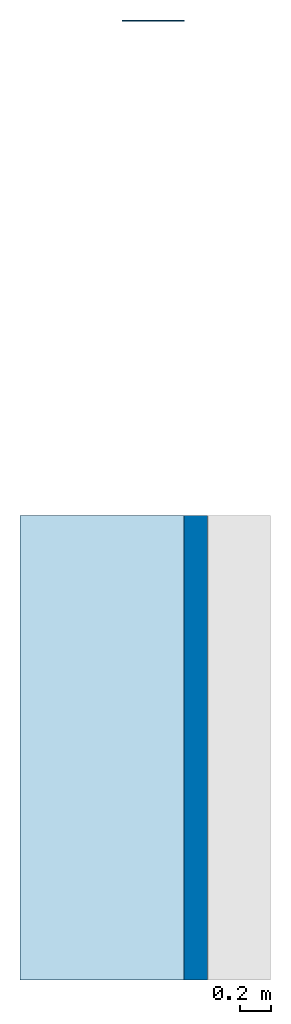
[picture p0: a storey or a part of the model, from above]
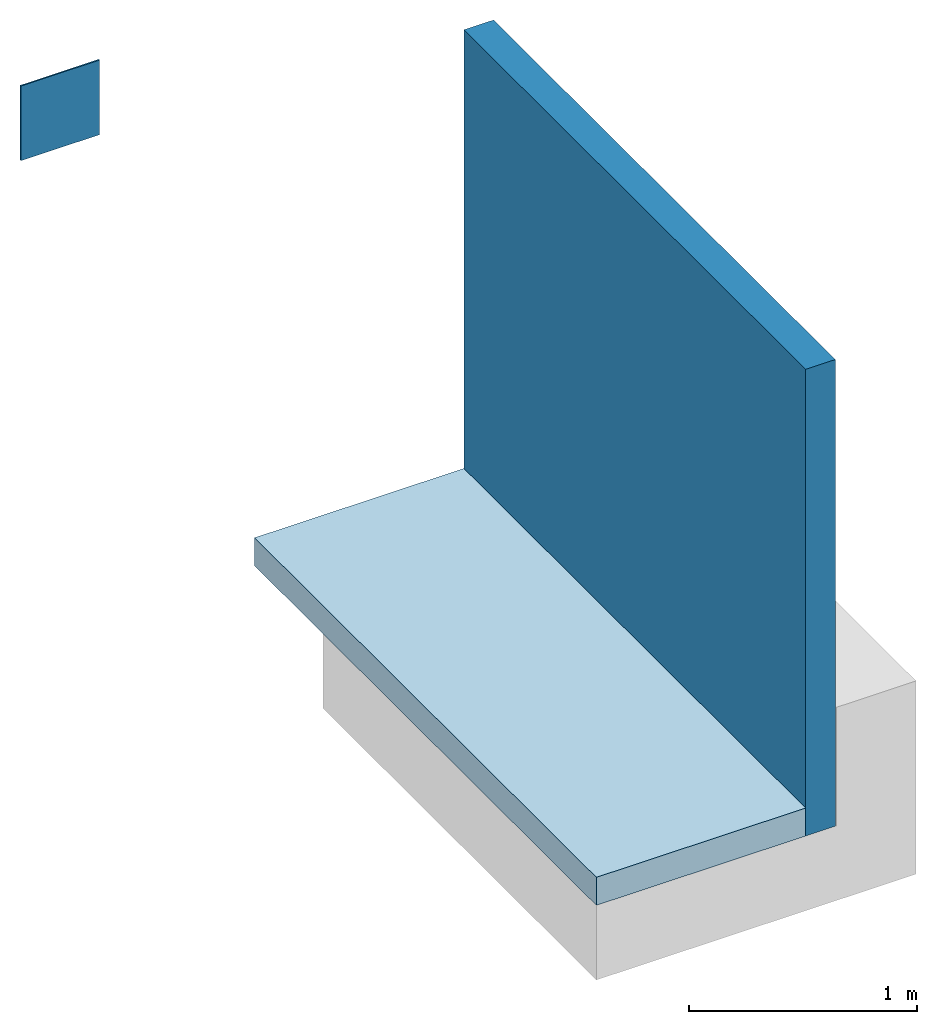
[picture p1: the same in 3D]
Properties of the parts of a building model (IFC2X3)

# File
Description: ViewDefinition [CoordinationView_V2.0], RevitIdentifiers [VersionGUID: a9bd6343-9679-42d1-a1b3-48d065d8c4a7, NumberOfSaves: 15], CoordinateReference [CoordinateBase: Coordenadas compartilhadas]
File name: 0001
Time: 2024-04-24T16:08:03
Written by: ODA IFC SDK 22.8
Made in: 22.1.50.17 - Exporter 22.6.2.0 - IU alternativa 22.6.2.0

# IfcProject, 0001
LongName: Cortina de Concreto (Face Externa) - Amphibia; Phase: Status do projeto

# IfcSite, Default
RefLatitude: 42, 21, 31, 181944; RefLongitude: -71, -3, -24, -263304; RefElevation: 0 m

# IfcBuilding
Pset_BuildingCommon - NumberOfStoreys: 1; IsLandmarked: no

# IfcBuildingStorey: Nível:Cabeça de 8 mm, ARQ Térreo
LongName: ARQ Térreo; Elevation: -0.0025238 m

# IfcBuildingElementProxy: IMPER:IMPER:433934, IMPER:IMPER:433934:IMPER:433934 : IMPER:IMPER:433934:291594
In: ARQ Térreo
Type - Material: #solo, #Geotextil, #Amphibia
Type - Pset_BuildingElementProxyCommon - Reference: IMPER
Type - Pset_QuantityTakeOff - Reference: IMPER
Type - Pset_ProvisionForVoid - Width: 0.952886 m; Height: 0.00103887 m; Depth: 2.6 m
Pset_BuildingElementProxyCommon - sets with these values: 2

# IfcSlab: Piso:Genérico 150 mm, Piso:Genérico 150 mm:305816
In: ARQ Térreo
Type - PredefinedType: FLOOR; Material: #concreto 0.15 m
Type - Pset_SlabCommon - IsExternal: no
Pset_QuantityTakeOff - Reference: Genérico 150 mm; sets with these values: 2
Pset_SlabCommon - LoadBearing: no; Reference: Genérico 150 mm; PitchAngle: 0 deg

# IfcWallStandardCase: Parede básica:IMPV_AMPHIBIA, Parede básica:IMPV_VP7000:459587
In: ARQ Térreo
Type - PredefinedType: STANDARD; Material: #Geotextil 0.003 m, #Amphibia 0.004 m
Type - Pset_WallCommon - IsExternal: yes; ThermalTransmittance: 16.4516 kg/K/s3
Pset_QuantityTakeOff - Reference: IMPV_VP7000; sets with these values: 2
Pset_WallCommon - ExtendToStructure: no; LoadBearing: no; Reference: IMPV_VP7000

# IfcWallStandardCase: Parede básica:Parede básica:Parede Concreto, Parede básica:Parede Concreto:395312
In: ARQ Térreo
Type - PredefinedType: STANDARD; Material: #concreto 0.15 m
Type - Pset_WallCommon - IsExternal: yes; ThermalTransmittance: 6.97333 kg/K/s3
Pset_QuantityTakeOff - Reference: Parede Concreto; sets with these values: 2
Pset_WallCommon - Reference: Parede Concreto; ExtendToStructure: no; LoadBearing: no
